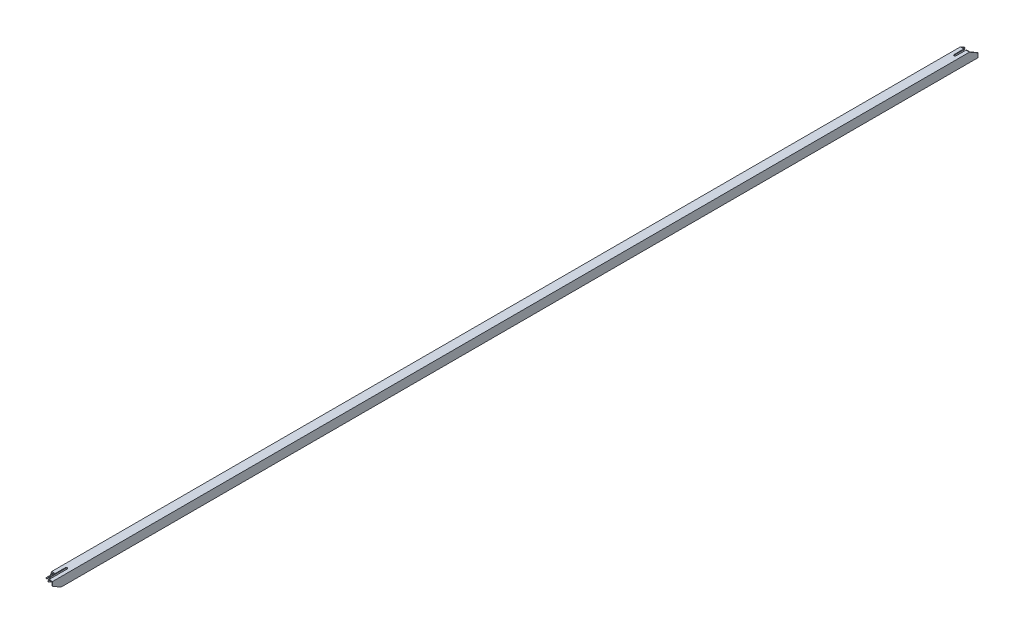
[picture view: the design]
ISO-10303-21;
HEADER;
FILE_DESCRIPTION(('STEP AP214'),'2;1');
FILE_NAME('part.step','',(''),(''),'','','');
FILE_SCHEMA(('AUTOMOTIVE_DESIGN { 1 0 10303 214 1 1 1 1 }'));
ENDSEC;
DATA;
#1=APPLICATION_CONTEXT('core data for automotive mechanical design processes');
#2=APPLICATION_PROTOCOL_DEFINITION('international standard','automotive_design',2000,#1);
#3=PRODUCT_CONTEXT('',#1,'mechanical');
#4=PRODUCT('Part','Part','',(#3));
#5=PRODUCT_RELATED_PRODUCT_CATEGORY('part','',(#4));
#6=PRODUCT_DEFINITION_FORMATION('','',#4);
#7=PRODUCT_DEFINITION_CONTEXT('part definition',#1,'design');
#8=PRODUCT_DEFINITION('design','',#6,#7);
#9=PRODUCT_DEFINITION_SHAPE('','',#8);
#10=(LENGTH_UNIT() NAMED_UNIT(*) SI_UNIT(.MILLI.,.METRE.));
#11=(NAMED_UNIT(*) PLANE_ANGLE_UNIT() SI_UNIT($,.RADIAN.));
#12=(NAMED_UNIT(*) SI_UNIT($,.STERADIAN.) SOLID_ANGLE_UNIT());
#13=UNCERTAINTY_MEASURE_WITH_UNIT(LENGTH_MEASURE(1.E-05),#10,'distance_accuracy_value','');
#14=(GEOMETRIC_REPRESENTATION_CONTEXT(3) GLOBAL_UNCERTAINTY_ASSIGNED_CONTEXT((#13)) GLOBAL_UNIT_ASSIGNED_CONTEXT((#10,
#11,#12)) REPRESENTATION_CONTEXT('',''));
#15=CARTESIAN_POINT('',(0.,0.,0.));
#16=DIRECTION('',(0.,0.,1.));
#17=DIRECTION('',(1.,0.,0.));
#18=AXIS2_PLACEMENT_3D('',#15,#16,#17);
#19=CARTESIAN_POINT('',(7.,-40.,5965.6450767));
#20=DIRECTION('',(1.,0.,0.));
#21=DIRECTION('',(0.,1.,0.));
#22=AXIS2_PLACEMENT_3D('',#19,#20,#21);
#23=PLANE('',#22);
#24=DIRECTION('',(0.,0.,1.));
#25=VECTOR('',#24,1.);
#26=CARTESIAN_POINT('',(7.,26.,2982.82253835));
#27=LINE('',#26,#25);
#28=CARTESIAN_POINT('',(7.,26.,5965.6450767));
#29=VERTEX_POINT('',#28);
#30=CARTESIAN_POINT('',(7.,26.,6085.6450767));
#31=VERTEX_POINT('',#30);
#32=EDGE_CURVE('E392',#29,#31,#27,.T.);
#33=ORIENTED_EDGE('',*,*,#32,.T.);
#34=DIRECTION('',(0.,1.,0.));
#35=VECTOR('',#34,1.);
#36=CARTESIAN_POINT('',(7.,-20.,6085.6450767));
#37=LINE('',#36,#35);
#38=CARTESIAN_POINT('',(7.,30.,6085.6450767));
#39=VERTEX_POINT('',#38);
#40=EDGE_CURVE('E538',#31,#39,#37,.T.);
#41=ORIENTED_EDGE('',*,*,#40,.T.);
#42=DIRECTION('',(0.,0.,1.));
#43=VECTOR('',#42,1.);
#44=CARTESIAN_POINT('',(7.,30.,2982.82253835));
#45=LINE('',#44,#43);
#46=CARTESIAN_POINT('',(7.,30.,5965.6450767));
#47=VERTEX_POINT('',#46);
#48=EDGE_CURVE('E533',#47,#39,#45,.T.);
#49=ORIENTED_EDGE('',*,*,#48,.F.);
#50=DIRECTION('',(0.,1.,0.));
#51=VECTOR('',#50,1.);
#52=CARTESIAN_POINT('',(7.,-40.,5965.6450767));
#53=LINE('',#52,#51);
#54=EDGE_CURVE('E10',#29,#47,#53,.T.);
#55=ORIENTED_EDGE('',*,*,#54,.F.);
#56=EDGE_LOOP('',(#33,#41,#49,#55));
#57=FACE_BOUND('',#56,.T.);
#58=ADVANCED_FACE('F16',(#57),#23,.F.);
#59=CARTESIAN_POINT('',(0.,-40.,5965.6450767));
#60=DIRECTION('',(0.,1.,0.));
#61=DIRECTION('',(0.,0.,1.));
#62=AXIS2_PLACEMENT_3D('',#59,#60,#61);
#63=CYLINDRICAL_SURFACE('',#62,7.);
#64=CARTESIAN_POINT('',(0.,30.,5965.6450767));
#65=DIRECTION('',(0.,1.,0.));
#66=DIRECTION('',(0.,0.,1.));
#67=AXIS2_PLACEMENT_3D('',#64,#65,#66);
#68=CIRCLE('',#67,7.);
#69=CARTESIAN_POINT('',(-7.,30.,5965.6450767));
#70=VERTEX_POINT('',#69);
#71=EDGE_CURVE('E530',#47,#70,#68,.T.);
#72=ORIENTED_EDGE('',*,*,#71,.T.);
#73=DIRECTION('',(0.,1.,0.));
#74=VECTOR('',#73,1.);
#75=CARTESIAN_POINT('',(-7.,-40.,5965.6450767));
#76=LINE('',#75,#74);
#77=CARTESIAN_POINT('',(-7.,26.,5965.6450767));
#78=VERTEX_POINT('',#77);
#79=EDGE_CURVE('E25',#78,#70,#76,.T.);
#80=ORIENTED_EDGE('',*,*,#79,.F.);
#81=CARTESIAN_POINT('',(0.,26.,5965.6450767));
#82=DIRECTION('',(0.,1.,0.));
#83=DIRECTION('',(0.,0.,1.));
#84=AXIS2_PLACEMENT_3D('',#81,#82,#83);
#85=CIRCLE('',#84,7.);
#86=EDGE_CURVE('E543',#29,#78,#85,.T.);
#87=ORIENTED_EDGE('',*,*,#86,.F.);
#88=ORIENTED_EDGE('',*,*,#54,.T.);
#89=EDGE_LOOP('',(#72,#80,#87,#88));
#90=FACE_BOUND('',#89,.T.);
#91=ADVANCED_FACE('F586',(#90),#63,.F.);
#92=CARTESIAN_POINT('',(-7.,-40.,5965.6450767));
#93=DIRECTION('',(1.,0.,0.));
#94=DIRECTION('',(0.,1.,0.));
#95=AXIS2_PLACEMENT_3D('',#92,#93,#94);
#96=PLANE('',#95);
#97=ORIENTED_EDGE('',*,*,#79,.T.);
#98=DIRECTION('',(0.,0.,1.));
#99=VECTOR('',#98,1.);
#100=CARTESIAN_POINT('',(-7.,30.,2982.82253835));
#101=LINE('',#100,#99);
#102=CARTESIAN_POINT('',(-7.,30.,6085.6450767));
#103=VERTEX_POINT('',#102);
#104=EDGE_CURVE('E466',#70,#103,#101,.T.);
#105=ORIENTED_EDGE('',*,*,#104,.T.);
#106=DIRECTION('',(0.,1.,0.));
#107=VECTOR('',#106,1.);
#108=CARTESIAN_POINT('',(-7.,-20.,6085.6450767));
#109=LINE('',#108,#107);
#110=CARTESIAN_POINT('',(-7.,26.,6085.6450767));
#111=VERTEX_POINT('',#110);
#112=EDGE_CURVE('E19',#111,#103,#109,.T.);
#113=ORIENTED_EDGE('',*,*,#112,.F.);
#114=DIRECTION('',(0.,0.,1.));
#115=VECTOR('',#114,1.);
#116=CARTESIAN_POINT('',(-7.,26.,2982.82253835));
#117=LINE('',#116,#115);
#118=EDGE_CURVE('E547',#78,#111,#117,.T.);
#119=ORIENTED_EDGE('',*,*,#118,.F.);
#120=EDGE_LOOP('',(#97,#105,#113,#119));
#121=FACE_BOUND('',#120,.T.);
#122=ADVANCED_FACE('F574',(#121),#96,.T.);
#123=CARTESIAN_POINT('',(0.,0.,6085.6450767));
#124=DIRECTION('',(0.,0.,1.));
#125=DIRECTION('',(1.,0.,0.));
#126=AXIS2_PLACEMENT_3D('',#123,#124,#125);
#127=PLANE('',#126);
#128=ORIENTED_EDGE('',*,*,#112,.T.);
#129=DIRECTION('',(-1.,0.,0.));
#130=VECTOR('',#129,1.);
#131=CARTESIAN_POINT('',(30.,30.,6085.6450767));
#132=LINE('',#131,#130);
#133=CARTESIAN_POINT('',(-13.,30.,6085.6450767));
#134=VERTEX_POINT('',#133);
#135=EDGE_CURVE('E462',#103,#134,#132,.T.);
#136=ORIENTED_EDGE('',*,*,#135,.T.);
#137=DIRECTION('',(0.,-1.,0.));
#138=VECTOR('',#137,1.);
#139=CARTESIAN_POINT('',(-13.,1310.449409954,6085.6450767));
#140=LINE('',#139,#138);
#141=CARTESIAN_POINT('',(-13.,26.,6085.6450767));
#142=VERTEX_POINT('',#141);
#143=EDGE_CURVE('E369',#134,#142,#140,.T.);
#144=ORIENTED_EDGE('',*,*,#143,.T.);
#145=DIRECTION('',(-1.,0.,0.));
#146=VECTOR('',#145,1.);
#147=CARTESIAN_POINT('',(26.,26.,6085.6450767));
#148=LINE('',#147,#146);
#149=EDGE_CURVE('E551',#111,#142,#148,.T.);
#150=ORIENTED_EDGE('',*,*,#149,.F.);
#151=EDGE_LOOP('',(#128,#136,#144,#150));
#152=FACE_BOUND('',#151,.T.);
#153=ADVANCED_FACE('F570',(#152),#127,.T.);
#154=CARTESIAN_POINT('',(-13.,2620.898819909,4549.014549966));
#155=DIRECTION('',(-1.,0.,0.));
#156=DIRECTION('',(0.,0.,1.));
#157=AXIS2_PLACEMENT_3D('',#154,#155,#156);
#158=PLANE('',#157);
#159=DIRECTION('',(0.,0.,-1.));
#160=VECTOR('',#159,1.);
#161=CARTESIAN_POINT('',(-13.,30.,2274.507274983));
#162=LINE('',#161,#160);
#163=CARTESIAN_POINT('',(-13.,30.,6033.874366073));
#164=VERTEX_POINT('',#163);
#165=EDGE_CURVE('E467',#134,#164,#162,.T.);
#166=ORIENTED_EDGE('',*,*,#165,.T.);
#167=DIRECTION('',(0.,-0.867615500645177,0.497235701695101));
#168=VECTOR('',#167,1.);
#169=CARTESIAN_POINT('',(-13.,2620.898819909,4549.014549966));
#170=LINE('',#169,#168);
#171=CARTESIAN_POINT('',(-13.,26.,6036.166790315));
#172=VERTEX_POINT('',#171);
#173=EDGE_CURVE('E368',#164,#172,#170,.T.);
#174=ORIENTED_EDGE('',*,*,#173,.T.);
#175=DIRECTION('',(0.,0.,-1.));
#176=VECTOR('',#175,1.);
#177=CARTESIAN_POINT('',(-13.,26.,2274.507274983));
#178=LINE('',#177,#176);
#179=EDGE_CURVE('E555',#142,#172,#178,.T.);
#180=ORIENTED_EDGE('',*,*,#179,.F.);
#181=ORIENTED_EDGE('',*,*,#143,.F.);
#182=EDGE_LOOP('',(#166,#174,#180,#181));
#183=FACE_BOUND('',#182,.T.);
#184=ADVANCED_FACE('F580',(#183),#158,.T.);
#185=CARTESIAN_POINT('',(-15.,2620.898819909,4549.014549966));
#186=DIRECTION('',(0.,-0.867615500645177,0.497235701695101));
#187=DIRECTION('',(-1.,0.,0.));
#188=AXIS2_PLACEMENT_3D('',#185,#186,#187);
#189=CYLINDRICAL_SURFACE('',#188,2.);
#190=CARTESIAN_POINT('',(-15.,26.,6036.166790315));
#191=DIRECTION('',(0.,-1.,0.));
#192=DIRECTION('',(0.,0.,1.));
#193=AXIS2_PLACEMENT_3D('',#190,#191,#192);
#194=ELLIPSE('',#193,2.305168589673,2.);
#195=CARTESIAN_POINT('',(-15.,26.,6033.861621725));
#196=VERTEX_POINT('',#195);
#197=EDGE_CURVE('E504',#196,#172,#194,.T.);
#198=ORIENTED_EDGE('',*,*,#197,.T.);
#199=ORIENTED_EDGE('',*,*,#173,.F.);
#200=CARTESIAN_POINT('',(-15.,30.,6033.874366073));
#201=DIRECTION('',(0.,-1.,0.));
#202=DIRECTION('',(0.,0.,1.));
#203=AXIS2_PLACEMENT_3D('',#200,#201,#202);
#204=ELLIPSE('',#203,2.305168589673,2.);
#205=CARTESIAN_POINT('',(-15.,30.,6031.569197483));
#206=VERTEX_POINT('',#205);
#207=EDGE_CURVE('E521',#206,#164,#204,.T.);
#208=ORIENTED_EDGE('',*,*,#207,.F.);
#209=DIRECTION('',(0.,-0.867615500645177,0.497235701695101));
#210=VECTOR('',#209,1.);
#211=CARTESIAN_POINT('',(-15.,2619.904348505,4547.279318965));
#212=LINE('',#211,#210);
#213=EDGE_CURVE('E478',#206,#196,#212,.T.);
#214=ORIENTED_EDGE('',*,*,#213,.T.);
#215=EDGE_LOOP('',(#198,#199,#208,#214));
#216=FACE_BOUND('',#215,.T.);
#217=ADVANCED_FACE('F779',(#216),#189,.F.);
#218=CARTESIAN_POINT('',(-7.,-40.,-1.));
#219=DIRECTION('',(1.,0.,0.));
#220=DIRECTION('',(0.,1.,0.));
#221=AXIS2_PLACEMENT_3D('',#218,#219,#220);
#222=PLANE('',#221);
#223=DIRECTION('',(0.,1.,0.));
#224=VECTOR('',#223,1.);
#225=CARTESIAN_POINT('',(-7.,-40.,120.));
#226=LINE('',#225,#224);
#227=CARTESIAN_POINT('',(-7.,26.,120.));
#228=VERTEX_POINT('',#227);
#229=CARTESIAN_POINT('',(-7.,30.,120.));
#230=VERTEX_POINT('',#229);
#231=EDGE_CURVE('E370',#228,#230,#226,.T.);
#232=ORIENTED_EDGE('',*,*,#231,.F.);
#233=DIRECTION('',(0.,0.,1.));
#234=VECTOR('',#233,1.);
#235=CARTESIAN_POINT('',(-7.,26.,-0.5));
#236=LINE('',#235,#234);
#237=CARTESIAN_POINT('',(-7.,26.,49.389058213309));
#238=VERTEX_POINT('',#237);
#239=EDGE_CURVE('E499',#238,#228,#236,.T.);
#240=ORIENTED_EDGE('',*,*,#239,.F.);
#241=DIRECTION('',(0.,-0.497235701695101,-0.867615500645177));
#242=VECTOR('',#241,1.);
#243=CARTESIAN_POINT('',(-7.,-6.895802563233,-8.01009497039));
#244=LINE('',#243,#242);
#245=CARTESIAN_POINT('',(-7.,30.,56.368569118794));
#246=VERTEX_POINT('',#245);
#247=EDGE_CURVE('E393',#246,#238,#244,.T.);
#248=ORIENTED_EDGE('',*,*,#247,.F.);
#249=DIRECTION('',(0.,0.,1.));
#250=VECTOR('',#249,1.);
#251=CARTESIAN_POINT('',(-7.,30.,-0.5));
#252=LINE('',#251,#250);
#253=EDGE_CURVE('E427',#246,#230,#252,.T.);
#254=ORIENTED_EDGE('',*,*,#253,.T.);
#255=EDGE_LOOP('',(#232,#240,#248,#254));
#256=FACE_BOUND('',#255,.T.);
#257=ADVANCED_FACE('F764',(#256),#222,.T.);
#258=CARTESIAN_POINT('',(0.,-40.,120.));
#259=DIRECTION('',(0.,1.,0.));
#260=DIRECTION('',(0.,0.,1.));
#261=AXIS2_PLACEMENT_3D('',#258,#259,#260);
#262=CYLINDRICAL_SURFACE('',#261,7.);
#263=CARTESIAN_POINT('',(0.,26.,120.));
#264=DIRECTION('',(0.,1.,0.));
#265=DIRECTION('',(0.,0.,1.));
#266=AXIS2_PLACEMENT_3D('',#263,#264,#265);
#267=CIRCLE('',#266,7.);
#268=CARTESIAN_POINT('',(0.,26.,127.));
#269=VERTEX_POINT('',#268);
#270=EDGE_CURVE('E503',#228,#269,#267,.T.);
#271=ORIENTED_EDGE('',*,*,#270,.F.);
#272=ORIENTED_EDGE('',*,*,#231,.T.);
#273=CARTESIAN_POINT('',(0.,30.,120.));
#274=DIRECTION('',(0.,1.,0.));
#275=DIRECTION('',(0.,0.,1.));
#276=AXIS2_PLACEMENT_3D('',#273,#274,#275);
#277=CIRCLE('',#276,7.);
#278=CARTESIAN_POINT('',(0.,30.,127.));
#279=VERTEX_POINT('',#278);
#280=EDGE_CURVE('E511',#230,#279,#277,.T.);
#281=ORIENTED_EDGE('',*,*,#280,.T.);
#282=DIRECTION('',(0.,1.,0.));
#283=VECTOR('',#282,1.);
#284=CARTESIAN_POINT('',(0.,-40.,127.));
#285=LINE('',#284,#283);
#286=EDGE_CURVE('E51',#269,#279,#285,.T.);
#287=ORIENTED_EDGE('',*,*,#286,.F.);
#288=EDGE_LOOP('',(#271,#272,#281,#287));
#289=FACE_BOUND('',#288,.T.);
#290=ADVANCED_FACE('F759',(#289),#262,.F.);
#291=CARTESIAN_POINT('',(0.,-40.,120.));
#292=DIRECTION('',(0.,1.,0.));
#293=DIRECTION('',(0.,0.,1.));
#294=AXIS2_PLACEMENT_3D('',#291,#292,#293);
#295=CYLINDRICAL_SURFACE('',#294,7.);
#296=DIRECTION('',(0.,1.,0.));
#297=VECTOR('',#296,1.);
#298=CARTESIAN_POINT('',(7.,-40.,120.));
#299=LINE('',#298,#297);
#300=CARTESIAN_POINT('',(7.,26.,120.));
#301=VERTEX_POINT('',#300);
#302=CARTESIAN_POINT('',(7.,30.,120.));
#303=VERTEX_POINT('',#302);
#304=EDGE_CURVE('E38',#301,#303,#299,.T.);
#305=ORIENTED_EDGE('',*,*,#304,.F.);
#306=CARTESIAN_POINT('',(0.,26.,120.));
#307=DIRECTION('',(0.,1.,0.));
#308=DIRECTION('',(0.,0.,1.));
#309=AXIS2_PLACEMENT_3D('',#306,#307,#308);
#310=CIRCLE('',#309,7.);
#311=EDGE_CURVE('E561',#269,#301,#310,.T.);
#312=ORIENTED_EDGE('',*,*,#311,.F.);
#313=ORIENTED_EDGE('',*,*,#286,.T.);
#314=CARTESIAN_POINT('',(0.,30.,120.));
#315=DIRECTION('',(0.,1.,0.));
#316=DIRECTION('',(0.,0.,1.));
#317=AXIS2_PLACEMENT_3D('',#314,#315,#316);
#318=CIRCLE('',#317,7.);
#319=EDGE_CURVE('E508',#279,#303,#318,.T.);
#320=ORIENTED_EDGE('',*,*,#319,.T.);
#321=EDGE_LOOP('',(#305,#312,#313,#320));
#322=FACE_BOUND('',#321,.T.);
#323=ADVANCED_FACE('F758',(#322),#295,.F.);
#324=CARTESIAN_POINT('',(7.,-40.,-1.));
#325=DIRECTION('',(1.,0.,0.));
#326=DIRECTION('',(0.,1.,0.));
#327=AXIS2_PLACEMENT_3D('',#324,#325,#326);
#328=PLANE('',#327);
#329=DIRECTION('',(0.,0.,1.));
#330=VECTOR('',#329,1.);
#331=CARTESIAN_POINT('',(7.,30.,-0.5));
#332=LINE('',#331,#330);
#333=CARTESIAN_POINT('',(7.,30.,56.368569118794));
#334=VERTEX_POINT('',#333);
#335=EDGE_CURVE('E498',#334,#303,#332,.T.);
#336=ORIENTED_EDGE('',*,*,#335,.F.);
#337=DIRECTION('',(0.,-0.497235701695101,-0.867615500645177));
#338=VECTOR('',#337,1.);
#339=CARTESIAN_POINT('',(7.,-6.895802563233,-8.01009497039));
#340=LINE('',#339,#338);
#341=CARTESIAN_POINT('',(7.,26.,49.389058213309));
#342=VERTEX_POINT('',#341);
#343=EDGE_CURVE('E490',#334,#342,#340,.T.);
#344=ORIENTED_EDGE('',*,*,#343,.T.);
#345=DIRECTION('',(0.,0.,1.));
#346=VECTOR('',#345,1.);
#347=CARTESIAN_POINT('',(7.,26.,-0.5));
#348=LINE('',#347,#346);
#349=EDGE_CURVE('E407',#342,#301,#348,.T.);
#350=ORIENTED_EDGE('',*,*,#349,.T.);
#351=ORIENTED_EDGE('',*,*,#304,.T.);
#352=EDGE_LOOP('',(#336,#344,#350,#351));
#353=FACE_BOUND('',#352,.T.);
#354=ADVANCED_FACE('F757',(#353),#328,.F.);
#355=CARTESIAN_POINT('',(26.,26.,0.));
#356=DIRECTION('',(0.,-1.,0.));
#357=DIRECTION('',(0.,0.,-1.));
#358=AXIS2_PLACEMENT_3D('',#355,#356,#357);
#359=PLANE('',#358);
#360=DIRECTION('',(-1.,0.,0.));
#361=VECTOR('',#360,1.);
#362=CARTESIAN_POINT('',(-9.5,26.,49.389058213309));
#363=LINE('',#362,#361);
#364=CARTESIAN_POINT('',(26.,26.,49.389058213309));
#365=VERTEX_POINT('',#364);
#366=EDGE_CURVE('E486',#365,#342,#363,.T.);
#367=ORIENTED_EDGE('',*,*,#366,.F.);
#368=DIRECTION('',(0.,0.,1.));
#369=VECTOR('',#368,1.);
#370=CARTESIAN_POINT('',(26.,26.,0.));
#371=LINE('',#370,#369);
#372=CARTESIAN_POINT('',(26.,26.,6085.6450767));
#373=VERTEX_POINT('',#372);
#374=EDGE_CURVE('E470',#365,#373,#371,.T.);
#375=ORIENTED_EDGE('',*,*,#374,.T.);
#376=DIRECTION('',(-1.,0.,0.));
#377=VECTOR('',#376,1.);
#378=CARTESIAN_POINT('',(26.,26.,6085.6450767));
#379=LINE('',#378,#377);
#380=EDGE_CURVE('E473',#373,#31,#379,.T.);
#381=ORIENTED_EDGE('',*,*,#380,.T.);
#382=ORIENTED_EDGE('',*,*,#32,.F.);
#383=ORIENTED_EDGE('',*,*,#86,.T.);
#384=ORIENTED_EDGE('',*,*,#118,.T.);
#385=ORIENTED_EDGE('',*,*,#149,.T.);
#386=ORIENTED_EDGE('',*,*,#179,.T.);
#387=ORIENTED_EDGE('',*,*,#197,.F.);
#388=DIRECTION('',(-1.,0.,0.));
#389=VECTOR('',#388,1.);
#390=CARTESIAN_POINT('',(-24.5,26.,6033.861621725));
#391=LINE('',#390,#389);
#392=CARTESIAN_POINT('',(-26.,26.,6033.861621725));
#393=VERTEX_POINT('',#392);
#394=EDGE_CURVE('E482',#196,#393,#391,.T.);
#395=ORIENTED_EDGE('',*,*,#394,.T.);
#396=DIRECTION('',(0.,0.,1.));
#397=VECTOR('',#396,1.);
#398=CARTESIAN_POINT('',(-26.,26.,0.));
#399=LINE('',#398,#397);
#400=CARTESIAN_POINT('',(-26.,26.,49.389058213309));
#401=VERTEX_POINT('',#400);
#402=EDGE_CURVE('E413',#401,#393,#399,.T.);
#403=ORIENTED_EDGE('',*,*,#402,.F.);
#404=DIRECTION('',(-1.,0.,0.));
#405=VECTOR('',#404,1.);
#406=CARTESIAN_POINT('',(-9.5,26.,49.389058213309));
#407=LINE('',#406,#405);
#408=EDGE_CURVE('E389',#238,#401,#407,.T.);
#409=ORIENTED_EDGE('',*,*,#408,.F.);
#410=ORIENTED_EDGE('',*,*,#239,.T.);
#411=ORIENTED_EDGE('',*,*,#270,.T.);
#412=ORIENTED_EDGE('',*,*,#311,.T.);
#413=ORIENTED_EDGE('',*,*,#349,.F.);
#414=EDGE_LOOP('',(#367,#375,#381,#382,#383,#384,#385,#386,#387,#395,#403,#409,#410,#411,#412,#413));
#415=FACE_BOUND('',#414,.T.);
#416=ADVANCED_FACE('F583',(#415),#359,.T.);
#417=CARTESIAN_POINT('',(-45.,-1.73523100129,0.994471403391));
#418=DIRECTION('',(0.,-0.867615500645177,0.497235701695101));
#419=DIRECTION('',(-1.,0.,0.));
#420=AXIS2_PLACEMENT_3D('',#417,#418,#419);
#421=PLANE('',#420);
#422=ORIENTED_EDGE('',*,*,#247,.T.);
#423=ORIENTED_EDGE('',*,*,#408,.T.);
#424=DIRECTION('',(0.,-0.497235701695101,-0.867615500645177));
#425=VECTOR('',#424,1.);
#426=CARTESIAN_POINT('',(-26.,1.478932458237,6.602793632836));
#427=LINE('',#426,#425);
#428=CARTESIAN_POINT('',(-26.,14.176311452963,28.758167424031));
#429=VERTEX_POINT('',#428);
#430=EDGE_CURVE('E418',#401,#429,#427,.T.);
#431=ORIENTED_EDGE('',*,*,#430,.T.);
#432=DIRECTION('',(-1.,0.,0.));
#433=VECTOR('',#432,1.);
#434=CARTESIAN_POINT('',(-30.,14.176311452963,28.758167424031));
#435=LINE('',#434,#433);
#436=CARTESIAN_POINT('',(-30.,14.176311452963,28.758167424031));
#437=VERTEX_POINT('',#436);
#438=EDGE_CURVE('E441',#429,#437,#435,.T.);
#439=ORIENTED_EDGE('',*,*,#438,.T.);
#440=DIRECTION('',(0.,-0.497235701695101,-0.867615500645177));
#441=VECTOR('',#440,1.);
#442=CARTESIAN_POINT('',(-30.,1.973419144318,7.465612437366));
#443=LINE('',#442,#441);
#444=CARTESIAN_POINT('',(-30.,30.,56.368569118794));
#445=VERTEX_POINT('',#444);
#446=EDGE_CURVE('E446',#445,#437,#443,.T.);
#447=ORIENTED_EDGE('',*,*,#446,.F.);
#448=DIRECTION('',(-1.,0.,0.));
#449=VECTOR('',#448,1.);
#450=CARTESIAN_POINT('',(-7.5,30.,56.368569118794));
#451=LINE('',#450,#449);
#452=EDGE_CURVE('E423',#246,#445,#451,.T.);
#453=ORIENTED_EDGE('',*,*,#452,.F.);
#454=EDGE_LOOP('',(#422,#423,#431,#439,#447,#453));
#455=FACE_BOUND('',#454,.T.);
#456=ADVANCED_FACE('F767',(#455),#421,.F.);
#457=CARTESIAN_POINT('',(-75.,2619.904348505,4547.279318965));
#458=DIRECTION('',(0.,0.497235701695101,0.867615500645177));
#459=DIRECTION('',(1.,0.,0.));
#460=AXIS2_PLACEMENT_3D('',#457,#458,#459);
#461=PLANE('',#460);
#462=ORIENTED_EDGE('',*,*,#213,.F.);
#463=DIRECTION('',(-1.,0.,0.));
#464=VECTOR('',#463,1.);
#465=CARTESIAN_POINT('',(-22.5,30.,6031.569197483));
#466=LINE('',#465,#464);
#467=CARTESIAN_POINT('',(-30.,30.,6031.569197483));
#468=VERTEX_POINT('',#467);
#469=EDGE_CURVE('E426',#206,#468,#466,.T.);
#470=ORIENTED_EDGE('',*,*,#469,.T.);
#471=DIRECTION('',(0.,-0.867615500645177,0.497235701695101));
#472=VECTOR('',#471,1.);
#473=CARTESIAN_POINT('',(-30.,2625.990005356,4543.791592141));
#474=LINE('',#473,#472);
#475=CARTESIAN_POINT('',(-30.,-14.17631145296,6056.886909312));
#476=VERTEX_POINT('',#475);
#477=EDGE_CURVE('E433',#468,#476,#474,.T.);
#478=ORIENTED_EDGE('',*,*,#477,.T.);
#479=DIRECTION('',(-1.,0.,0.));
#480=VECTOR('',#479,1.);
#481=CARTESIAN_POINT('',(-60.,-14.17631145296,6056.886909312));
#482=LINE('',#481,#480);
#483=CARTESIAN_POINT('',(-26.,-14.17631145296,6056.886909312));
#484=VERTEX_POINT('',#483);
#485=EDGE_CURVE('E422',#484,#476,#482,.T.);
#486=ORIENTED_EDGE('',*,*,#485,.F.);
#487=DIRECTION('',(0.,-0.867615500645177,0.497235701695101));
#488=VECTOR('',#487,1.);
#489=CARTESIAN_POINT('',(-26.,2624.484492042,4544.654410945));
#490=LINE('',#489,#488);
#491=EDGE_CURVE('E417',#393,#484,#490,.T.);
#492=ORIENTED_EDGE('',*,*,#491,.F.);
#493=ORIENTED_EDGE('',*,*,#394,.F.);
#494=EDGE_LOOP('',(#462,#470,#478,#486,#492,#493));
#495=FACE_BOUND('',#494,.T.);
#496=ADVANCED_FACE('F774',(#495),#461,.T.);
#497=CARTESIAN_POINT('',(-26.,26.,0.));
#498=DIRECTION('',(1.,0.,0.));
#499=DIRECTION('',(0.,1.,0.));
#500=AXIS2_PLACEMENT_3D('',#497,#498,#499);
#501=PLANE('',#500);
#502=ORIENTED_EDGE('',*,*,#430,.F.);
#503=ORIENTED_EDGE('',*,*,#402,.T.);
#504=ORIENTED_EDGE('',*,*,#491,.T.);
#505=DIRECTION('',(0.,0.497235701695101,0.867615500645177));
#506=VECTOR('',#505,1.);
#507=CARTESIAN_POINT('',(-26.,-1330.625700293,3759.843692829));
#508=LINE('',#507,#506);
#509=CARTESIAN_POINT('',(-26.,-26.,6036.256018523));
#510=VERTEX_POINT('',#509);
#511=EDGE_CURVE('E412',#510,#484,#508,.T.);
#512=ORIENTED_EDGE('',*,*,#511,.F.);
#513=DIRECTION('',(0.,0.,1.));
#514=VECTOR('',#513,1.);
#515=CARTESIAN_POINT('',(-26.,-26.,0.));
#516=LINE('',#515,#514);
#517=CARTESIAN_POINT('',(-26.,-26.,51.783455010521));
#518=VERTEX_POINT('',#517);
#519=EDGE_CURVE('E428',#518,#510,#516,.T.);
#520=ORIENTED_EDGE('',*,*,#519,.F.);
#521=DIRECTION('',(0.,0.867615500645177,-0.497235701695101));
#522=VECTOR('',#521,1.);
#523=CARTESIAN_POINT('',(-26.,30.903071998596,19.171959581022));
#524=LINE('',#523,#522);
#525=EDGE_CURVE('E449',#518,#429,#524,.T.);
#526=ORIENTED_EDGE('',*,*,#525,.T.);
#527=EDGE_LOOP('',(#502,#503,#504,#512,#520,#526));
#528=FACE_BOUND('',#527,.T.);
#529=ADVANCED_FACE('F920',(#528),#501,.T.);
#530=CARTESIAN_POINT('',(0.,0.,6085.6450767));
#531=DIRECTION('',(0.,0.,1.));
#532=DIRECTION('',(1.,0.,0.));
#533=AXIS2_PLACEMENT_3D('',#530,#531,#532);
#534=PLANE('',#533);
#535=DIRECTION('',(0.,1.,0.));
#536=VECTOR('',#535,1.);
#537=CARTESIAN_POINT('',(26.,-26.,6085.6450767));
#538=LINE('',#537,#536);
#539=CARTESIAN_POINT('',(26.,2.305168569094,6085.6450767));
#540=VERTEX_POINT('',#539);
#541=EDGE_CURVE('E339',#540,#373,#538,.T.);
#542=ORIENTED_EDGE('',*,*,#541,.F.);
#543=DIRECTION('',(-1.,0.,0.));
#544=VECTOR('',#543,1.);
#545=CARTESIAN_POINT('',(-22.5,2.305168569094,6085.6450767));
#546=LINE('',#545,#544);
#547=CARTESIAN_POINT('',(30.,2.305168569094,6085.6450767));
#548=VERTEX_POINT('',#547);
#549=EDGE_CURVE('E332',#548,#540,#546,.T.);
#550=ORIENTED_EDGE('',*,*,#549,.F.);
#551=DIRECTION('',(0.,1.,0.));
#552=VECTOR('',#551,1.);
#553=CARTESIAN_POINT('',(30.,-30.,6085.6450767));
#554=LINE('',#553,#552);
#555=CARTESIAN_POINT('',(30.,30.,6085.6450767));
#556=VERTEX_POINT('',#555);
#557=EDGE_CURVE('E336',#548,#556,#554,.T.);
#558=ORIENTED_EDGE('',*,*,#557,.T.);
#559=DIRECTION('',(-1.,0.,0.));
#560=VECTOR('',#559,1.);
#561=CARTESIAN_POINT('',(30.,30.,6085.6450767));
#562=LINE('',#561,#560);
#563=EDGE_CURVE('E326',#556,#39,#562,.T.);
#564=ORIENTED_EDGE('',*,*,#563,.T.);
#565=ORIENTED_EDGE('',*,*,#40,.F.);
#566=ORIENTED_EDGE('',*,*,#380,.F.);
#567=EDGE_LOOP('',(#542,#550,#558,#564,#565,#566));
#568=FACE_BOUND('',#567,.T.);
#569=ADVANCED_FACE('F334',(#568),#534,.T.);
#570=CARTESIAN_POINT('',(30.,30.,0.));
#571=DIRECTION('',(0.,-1.,0.));
#572=DIRECTION('',(0.,0.,-1.));
#573=AXIS2_PLACEMENT_3D('',#570,#571,#572);
#574=PLANE('',#573);
#575=ORIENTED_EDGE('',*,*,#335,.T.);
#576=ORIENTED_EDGE('',*,*,#319,.F.);
#577=ORIENTED_EDGE('',*,*,#280,.F.);
#578=ORIENTED_EDGE('',*,*,#253,.F.);
#579=ORIENTED_EDGE('',*,*,#452,.T.);
#580=DIRECTION('',(0.,0.,1.));
#581=VECTOR('',#580,1.);
#582=CARTESIAN_POINT('',(-30.,30.,0.));
#583=LINE('',#582,#581);
#584=EDGE_CURVE('E436',#445,#468,#583,.T.);
#585=ORIENTED_EDGE('',*,*,#584,.T.);
#586=ORIENTED_EDGE('',*,*,#469,.F.);
#587=ORIENTED_EDGE('',*,*,#207,.T.);
#588=ORIENTED_EDGE('',*,*,#165,.F.);
#589=ORIENTED_EDGE('',*,*,#135,.F.);
#590=ORIENTED_EDGE('',*,*,#104,.F.);
#591=ORIENTED_EDGE('',*,*,#71,.F.);
#592=ORIENTED_EDGE('',*,*,#48,.T.);
#593=ORIENTED_EDGE('',*,*,#563,.F.);
#594=DIRECTION('',(0.,0.,1.));
#595=VECTOR('',#594,1.);
#596=CARTESIAN_POINT('',(30.,30.,0.));
#597=LINE('',#596,#595);
#598=CARTESIAN_POINT('',(30.,30.,56.368569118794));
#599=VERTEX_POINT('',#598);
#600=EDGE_CURVE('E358',#599,#556,#597,.T.);
#601=ORIENTED_EDGE('',*,*,#600,.F.);
#602=DIRECTION('',(-1.,0.,0.));
#603=VECTOR('',#602,1.);
#604=CARTESIAN_POINT('',(-7.5,30.,56.368569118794));
#605=LINE('',#604,#603);
#606=EDGE_CURVE('E494',#599,#334,#605,.T.);
#607=ORIENTED_EDGE('',*,*,#606,.T.);
#608=EDGE_LOOP('',(#575,#576,#577,#578,#579,#585,#586,#587,#588,#589,#590,#591,#592,#593,#601,#607));
#609=FACE_BOUND('',#608,.T.);
#610=ADVANCED_FACE('F576',(#609),#574,.F.);
#611=CARTESIAN_POINT('',(-45.,-1.73523100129,0.994471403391));
#612=DIRECTION('',(0.,-0.867615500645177,0.497235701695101));
#613=DIRECTION('',(-1.,0.,0.));
#614=AXIS2_PLACEMENT_3D('',#611,#612,#613);
#615=PLANE('',#614);
#616=ORIENTED_EDGE('',*,*,#366,.T.);
#617=ORIENTED_EDGE('',*,*,#343,.F.);
#618=ORIENTED_EDGE('',*,*,#606,.F.);
#619=DIRECTION('',(0.,0.497235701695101,0.867615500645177));
#620=VECTOR('',#619,1.);
#621=CARTESIAN_POINT('',(30.,-5.443881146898,-5.476669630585));
#622=LINE('',#621,#620);
#623=CARTESIAN_POINT('',(30.,-2.305168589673,0.));
#624=VERTEX_POINT('',#623);
#625=EDGE_CURVE('E364',#624,#599,#622,.T.);
#626=ORIENTED_EDGE('',*,*,#625,.F.);
#627=DIRECTION('',(1.,0.,0.));
#628=VECTOR('',#627,1.);
#629=CARTESIAN_POINT('',(-22.5,-2.305168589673,0.));
#630=LINE('',#629,#628);
#631=CARTESIAN_POINT('',(26.,-2.305168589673,0.));
#632=VERTEX_POINT('',#631);
#633=EDGE_CURVE('E733',#632,#624,#630,.T.);
#634=ORIENTED_EDGE('',*,*,#633,.F.);
#635=DIRECTION('',(0.,0.497235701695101,0.867615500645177));
#636=VECTOR('',#635,1.);
#637=CARTESIAN_POINT('',(26.,-4.949394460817,-4.613850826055));
#638=LINE('',#637,#636);
#639=EDGE_CURVE('E477',#632,#365,#638,.T.);
#640=ORIENTED_EDGE('',*,*,#639,.T.);
#641=EDGE_LOOP('',(#616,#617,#618,#626,#634,#640));
#642=FACE_BOUND('',#641,.T.);
#643=ADVANCED_FACE('F752',(#642),#615,.F.);
#644=CARTESIAN_POINT('',(26.,-26.,0.));
#645=DIRECTION('',(-1.,0.,0.));
#646=DIRECTION('',(0.,0.,1.));
#647=AXIS2_PLACEMENT_3D('',#644,#645,#646);
#648=PLANE('',#647);
#649=DIRECTION('',(0.,1.,0.));
#650=VECTOR('',#649,1.);
#651=CARTESIAN_POINT('',(26.,-26.,0.));
#652=LINE('',#651,#650);
#653=CARTESIAN_POINT('',(26.,-26.,0.));
#654=VERTEX_POINT('',#653);
#655=EDGE_CURVE('E729',#654,#632,#652,.T.);
#656=ORIENTED_EDGE('',*,*,#655,.F.);
#657=DIRECTION('',(0.,0.,1.));
#658=VECTOR('',#657,1.);
#659=CARTESIAN_POINT('',(26.,-26.,0.));
#660=LINE('',#659,#658);
#661=CARTESIAN_POINT('',(26.,-26.,6036.256018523));
#662=VERTEX_POINT('',#661);
#663=EDGE_CURVE('E431',#654,#662,#660,.T.);
#664=ORIENTED_EDGE('',*,*,#663,.T.);
#665=DIRECTION('',(0.,-0.497235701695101,-0.867615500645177));
#666=VECTOR('',#665,1.);
#667=CARTESIAN_POINT('',(26.,-1337.054027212,3748.627048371));
#668=LINE('',#667,#666);
#669=EDGE_CURVE('E344',#540,#662,#668,.T.);
#670=ORIENTED_EDGE('',*,*,#669,.F.);
#671=ORIENTED_EDGE('',*,*,#541,.T.);
#672=ORIENTED_EDGE('',*,*,#374,.F.);
#673=ORIENTED_EDGE('',*,*,#639,.F.);
#674=EDGE_LOOP('',(#656,#664,#670,#671,#672,#673));
#675=FACE_BOUND('',#674,.T.);
#676=ADVANCED_FACE('F944',(#675),#648,.T.);
#677=CARTESIAN_POINT('',(-26.,-26.,0.));
#678=DIRECTION('',(0.,1.,0.));
#679=DIRECTION('',(1.,0.,0.));
#680=AXIS2_PLACEMENT_3D('',#677,#678,#679);
#681=PLANE('',#680);
#682=DIRECTION('',(1.,0.,0.));
#683=VECTOR('',#682,1.);
#684=CARTESIAN_POINT('',(-26.,-26.,0.));
#685=LINE('',#684,#683);
#686=CARTESIAN_POINT('',(-13.,-26.,0.));
#687=VERTEX_POINT('',#686);
#688=CARTESIAN_POINT('',(-7.,-26.,0.));
#689=VERTEX_POINT('',#688);
#690=EDGE_CURVE('E686',#687,#689,#685,.T.);
#691=ORIENTED_EDGE('',*,*,#690,.F.);
#692=DIRECTION('',(0.,0.,1.));
#693=VECTOR('',#692,1.);
#694=CARTESIAN_POINT('',(-13.,-26.,-15.99764671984));
#695=LINE('',#694,#693);
#696=CARTESIAN_POINT('',(-13.,-26.,49.478286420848));
#697=VERTEX_POINT('',#696);
#698=EDGE_CURVE('E432',#687,#697,#695,.T.);
#699=ORIENTED_EDGE('',*,*,#698,.T.);
#700=CARTESIAN_POINT('',(-15.,-26.,49.478286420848));
#701=DIRECTION('',(0.,1.,0.));
#702=DIRECTION('',(0.,0.,1.));
#703=AXIS2_PLACEMENT_3D('',#700,#701,#702);
#704=ELLIPSE('',#703,2.305168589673,2.);
#705=CARTESIAN_POINT('',(-15.,-26.,51.783455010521));
#706=VERTEX_POINT('',#705);
#707=EDGE_CURVE('E453',#706,#697,#704,.T.);
#708=ORIENTED_EDGE('',*,*,#707,.F.);
#709=DIRECTION('',(-1.,0.,0.));
#710=VECTOR('',#709,1.);
#711=CARTESIAN_POINT('',(-20.5,-26.,51.783455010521));
#712=LINE('',#711,#710);
#713=EDGE_CURVE('E442',#706,#518,#712,.T.);
#714=ORIENTED_EDGE('',*,*,#713,.T.);
#715=ORIENTED_EDGE('',*,*,#519,.T.);
#716=DIRECTION('',(-1.,0.,0.));
#717=VECTOR('',#716,1.);
#718=CARTESIAN_POINT('',(-35.5,-26.,6036.256018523));
#719=LINE('',#718,#717);
#720=CARTESIAN_POINT('',(-7.,-26.,6036.256018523));
#721=VERTEX_POINT('',#720);
#722=EDGE_CURVE('E408',#721,#510,#719,.T.);
#723=ORIENTED_EDGE('',*,*,#722,.F.);
#724=DIRECTION('',(0.,0.,-1.));
#725=VECTOR('',#724,1.);
#726=CARTESIAN_POINT('',(-7.,-26.,2982.82253835));
#727=LINE('',#726,#725);
#728=CARTESIAN_POINT('',(-7.,-26.,5965.6450767));
#729=VERTEX_POINT('',#728);
#730=EDGE_CURVE('E400',#721,#729,#727,.T.);
#731=ORIENTED_EDGE('',*,*,#730,.T.);
#732=CARTESIAN_POINT('',(0.,-26.,5965.6450767));
#733=DIRECTION('',(0.,1.,0.));
#734=DIRECTION('',(0.,0.,1.));
#735=AXIS2_PLACEMENT_3D('',#732,#733,#734);
#736=CIRCLE('',#735,7.);
#737=CARTESIAN_POINT('',(7.,-26.,5965.6450767));
#738=VERTEX_POINT('',#737);
#739=EDGE_CURVE('E397',#738,#729,#736,.T.);
#740=ORIENTED_EDGE('',*,*,#739,.F.);
#741=DIRECTION('',(0.,0.,-1.));
#742=VECTOR('',#741,1.);
#743=CARTESIAN_POINT('',(7.,-26.,2982.82253835));
#744=LINE('',#743,#742);
#745=CARTESIAN_POINT('',(7.,-26.,6036.256018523));
#746=VERTEX_POINT('',#745);
#747=EDGE_CURVE('E388',#746,#738,#744,.T.);
#748=ORIENTED_EDGE('',*,*,#747,.F.);
#749=DIRECTION('',(-1.,0.,0.));
#750=VECTOR('',#749,1.);
#751=CARTESIAN_POINT('',(-35.5,-26.,6036.256018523));
#752=LINE('',#751,#750);
#753=EDGE_CURVE('E376',#662,#746,#752,.T.);
#754=ORIENTED_EDGE('',*,*,#753,.F.);
#755=ORIENTED_EDGE('',*,*,#663,.F.);
#756=DIRECTION('',(1.,0.,0.));
#757=VECTOR('',#756,1.);
#758=CARTESIAN_POINT('',(-26.,-26.,0.));
#759=LINE('',#758,#757);
#760=CARTESIAN_POINT('',(7.,-26.,0.));
#761=VERTEX_POINT('',#760);
#762=EDGE_CURVE('E681',#761,#654,#759,.T.);
#763=ORIENTED_EDGE('',*,*,#762,.F.);
#764=DIRECTION('',(0.,0.,-1.));
#765=VECTOR('',#764,1.);
#766=CARTESIAN_POINT('',(7.,-26.,-0.5));
#767=LINE('',#766,#765);
#768=CARTESIAN_POINT('',(7.,-26.,120.));
#769=VERTEX_POINT('',#768);
#770=EDGE_CURVE('E618',#769,#761,#767,.T.);
#771=ORIENTED_EDGE('',*,*,#770,.F.);
#772=CARTESIAN_POINT('',(0.,-26.,120.));
#773=DIRECTION('',(0.,1.,0.));
#774=DIRECTION('',(0.,0.,1.));
#775=AXIS2_PLACEMENT_3D('',#772,#773,#774);
#776=CIRCLE('',#775,7.);
#777=CARTESIAN_POINT('',(0.,-26.,127.));
#778=VERTEX_POINT('',#777);
#779=EDGE_CURVE('E614',#778,#769,#776,.T.);
#780=ORIENTED_EDGE('',*,*,#779,.F.);
#781=CARTESIAN_POINT('',(0.,-26.,120.));
#782=DIRECTION('',(0.,1.,0.));
#783=DIRECTION('',(0.,0.,1.));
#784=AXIS2_PLACEMENT_3D('',#781,#782,#783);
#785=CIRCLE('',#784,7.);
#786=CARTESIAN_POINT('',(-7.,-26.,120.));
#787=VERTEX_POINT('',#786);
#788=EDGE_CURVE('E712',#787,#778,#785,.T.);
#789=ORIENTED_EDGE('',*,*,#788,.F.);
#790=DIRECTION('',(0.,0.,-1.));
#791=VECTOR('',#790,1.);
#792=CARTESIAN_POINT('',(-7.,-26.,-0.5));
#793=LINE('',#792,#791);
#794=EDGE_CURVE('E706',#787,#689,#793,.T.);
#795=ORIENTED_EDGE('',*,*,#794,.T.);
#796=EDGE_LOOP('',(#691,#699,#708,#714,#715,#723,#731,#740,#748,#754,#755,#763,#771,#780,#789,#795));
#797=FACE_BOUND('',#796,.T.);
#798=ADVANCED_FACE('F808',(#797),#681,.T.);
#799=CARTESIAN_POINT('',(-13.,-4.505685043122,-31.99529343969));
#800=DIRECTION('',(-1.,0.,0.));
#801=DIRECTION('',(0.,0.,1.));
#802=AXIS2_PLACEMENT_3D('',#799,#800,#801);
#803=PLANE('',#802);
#804=DIRECTION('',(0.,-0.867615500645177,0.497235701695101));
#805=VECTOR('',#804,1.);
#806=CARTESIAN_POINT('',(-13.,25.328457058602,20.061636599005));
#807=LINE('',#806,#805);
#808=CARTESIAN_POINT('',(-13.,-30.,51.770710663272));
#809=VERTEX_POINT('',#808);
#810=EDGE_CURVE('E457',#697,#809,#807,.T.);
#811=ORIENTED_EDGE('',*,*,#810,.F.);
#812=ORIENTED_EDGE('',*,*,#698,.F.);
#813=DIRECTION('',(0.,-1.,0.));
#814=VECTOR('',#813,1.);
#815=CARTESIAN_POINT('',(-13.,-2.252842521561,0.));
#816=LINE('',#815,#814);
#817=CARTESIAN_POINT('',(-13.,-30.,0.));
#818=VERTEX_POINT('',#817);
#819=EDGE_CURVE('E694',#687,#818,#816,.T.);
#820=ORIENTED_EDGE('',*,*,#819,.T.);
#821=DIRECTION('',(0.,0.,1.));
#822=VECTOR('',#821,1.);
#823=CARTESIAN_POINT('',(-13.,-30.,-15.99764671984));
#824=LINE('',#823,#822);
#825=EDGE_CURVE('E667',#818,#809,#824,.T.);
#826=ORIENTED_EDGE('',*,*,#825,.T.);
#827=EDGE_LOOP('',(#811,#812,#820,#826));
#828=FACE_BOUND('',#827,.T.);
#829=ADVANCED_FACE('F793',(#828),#803,.T.);
#830=CARTESIAN_POINT('',(-15.,25.328457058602,20.061636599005));
#831=DIRECTION('',(0.,-0.867615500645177,0.497235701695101));
#832=DIRECTION('',(0.,-0.497235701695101,-0.867615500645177));
#833=AXIS2_PLACEMENT_3D('',#830,#831,#832);
#834=CYLINDRICAL_SURFACE('',#833,2.);
#835=CARTESIAN_POINT('',(-15.,-30.,51.770710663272));
#836=DIRECTION('',(0.,1.,0.));
#837=DIRECTION('',(0.,0.,1.));
#838=AXIS2_PLACEMENT_3D('',#835,#836,#837);
#839=ELLIPSE('',#838,2.305168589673,2.);
#840=CARTESIAN_POINT('',(-15.,-30.,54.075879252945));
#841=VERTEX_POINT('',#840);
#842=EDGE_CURVE('E663',#841,#809,#839,.T.);
#843=ORIENTED_EDGE('',*,*,#842,.F.);
#844=DIRECTION('',(0.,-0.867615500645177,0.497235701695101));
#845=VECTOR('',#844,1.);
#846=CARTESIAN_POINT('',(-15.,26.322928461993,21.796867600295));
#847=LINE('',#846,#845);
#848=EDGE_CURVE('E438',#706,#841,#847,.T.);
#849=ORIENTED_EDGE('',*,*,#848,.F.);
#850=ORIENTED_EDGE('',*,*,#707,.T.);
#851=ORIENTED_EDGE('',*,*,#810,.T.);
#852=EDGE_LOOP('',(#843,#849,#850,#851));
#853=FACE_BOUND('',#852,.T.);
#854=ADVANCED_FACE('F804',(#853),#834,.F.);
#855=CARTESIAN_POINT('',(-15.,26.322928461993,21.796867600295));
#856=DIRECTION('',(0.,-0.497235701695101,-0.867615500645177));
#857=DIRECTION('',(0.,-0.867615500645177,0.497235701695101));
#858=AXIS2_PLACEMENT_3D('',#855,#856,#857);
#859=PLANE('',#858);
#860=ORIENTED_EDGE('',*,*,#713,.F.);
#861=ORIENTED_EDGE('',*,*,#848,.T.);
#862=DIRECTION('',(-1.,0.,0.));
#863=VECTOR('',#862,1.);
#864=CARTESIAN_POINT('',(-22.5,-30.,54.075879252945));
#865=LINE('',#864,#863);
#866=CARTESIAN_POINT('',(-30.,-30.,54.075879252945));
#867=VERTEX_POINT('',#866);
#868=EDGE_CURVE('E633',#841,#867,#865,.T.);
#869=ORIENTED_EDGE('',*,*,#868,.T.);
#870=DIRECTION('',(0.,0.867615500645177,-0.497235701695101));
#871=VECTOR('',#870,1.);
#872=CARTESIAN_POINT('',(-30.,32.408585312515,18.309140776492));
#873=LINE('',#872,#871);
#874=EDGE_CURVE('E437',#867,#437,#873,.T.);
#875=ORIENTED_EDGE('',*,*,#874,.T.);
#876=ORIENTED_EDGE('',*,*,#438,.F.);
#877=ORIENTED_EDGE('',*,*,#525,.F.);
#878=EDGE_LOOP('',(#860,#861,#869,#875,#876,#877));
#879=FACE_BOUND('',#878,.T.);
#880=ADVANCED_FACE('F963',(#879),#859,.T.);
#881=CARTESIAN_POINT('',(-30.,30.,0.));
#882=DIRECTION('',(1.,0.,0.));
#883=DIRECTION('',(0.,1.,0.));
#884=AXIS2_PLACEMENT_3D('',#881,#882,#883);
#885=PLANE('',#884);
#886=ORIENTED_EDGE('',*,*,#874,.F.);
#887=DIRECTION('',(0.,0.,1.));
#888=VECTOR('',#887,1.);
#889=CARTESIAN_POINT('',(-30.,-30.,0.));
#890=LINE('',#889,#888);
#891=CARTESIAN_POINT('',(-30.,-30.,6029.276507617));
#892=VERTEX_POINT('',#891);
#893=EDGE_CURVE('E629',#867,#892,#890,.T.);
#894=ORIENTED_EDGE('',*,*,#893,.T.);
#895=DIRECTION('',(0.,0.497235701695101,0.867615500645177));
#896=VECTOR('',#895,1.);
#897=CARTESIAN_POINT('',(-30.,-1330.131213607,3760.706511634));
#898=LINE('',#897,#896);
#899=EDGE_CURVE('E702',#892,#476,#898,.T.);
#900=ORIENTED_EDGE('',*,*,#899,.T.);
#901=ORIENTED_EDGE('',*,*,#477,.F.);
#902=ORIENTED_EDGE('',*,*,#584,.F.);
#903=ORIENTED_EDGE('',*,*,#446,.T.);
#904=EDGE_LOOP('',(#886,#894,#900,#901,#902,#903));
#905=FACE_BOUND('',#904,.T.);
#906=ADVANCED_FACE('F772',(#905),#885,.F.);
#907=CARTESIAN_POINT('',(-45.,-44.01045355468,6004.829979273));
#908=DIRECTION('',(0.,0.867615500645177,-0.497235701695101));
#909=DIRECTION('',(-1.,0.,0.));
#910=AXIS2_PLACEMENT_3D('',#907,#908,#909);
#911=PLANE('',#910);
#912=ORIENTED_EDGE('',*,*,#722,.T.);
#913=ORIENTED_EDGE('',*,*,#511,.T.);
#914=ORIENTED_EDGE('',*,*,#485,.T.);
#915=ORIENTED_EDGE('',*,*,#899,.F.);
#916=DIRECTION('',(-1.,0.,0.));
#917=VECTOR('',#916,1.);
#918=CARTESIAN_POINT('',(-37.5,-30.,6029.276507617));
#919=LINE('',#918,#917);
#920=CARTESIAN_POINT('',(-7.,-30.,6029.276507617));
#921=VERTEX_POINT('',#920);
#922=EDGE_CURVE('E634',#921,#892,#919,.T.);
#923=ORIENTED_EDGE('',*,*,#922,.F.);
#924=DIRECTION('',(0.,0.497235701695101,0.867615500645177));
#925=VECTOR('',#924,1.);
#926=CARTESIAN_POINT('',(-7.,-51.96704228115,5990.946704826));
#927=LINE('',#926,#925);
#928=EDGE_CURVE('E403',#921,#721,#927,.T.);
#929=ORIENTED_EDGE('',*,*,#928,.T.);
#930=EDGE_LOOP('',(#912,#913,#914,#915,#923,#929));
#931=FACE_BOUND('',#930,.T.);
#932=ADVANCED_FACE('F962',(#931),#911,.F.);
#933=CARTESIAN_POINT('',(-7.,-40.,5965.6450767));
#934=DIRECTION('',(1.,0.,0.));
#935=DIRECTION('',(0.,1.,0.));
#936=AXIS2_PLACEMENT_3D('',#933,#934,#935);
#937=PLANE('',#936);
#938=ORIENTED_EDGE('',*,*,#730,.F.);
#939=ORIENTED_EDGE('',*,*,#928,.F.);
#940=DIRECTION('',(0.,0.,-1.));
#941=VECTOR('',#940,1.);
#942=CARTESIAN_POINT('',(-7.,-30.,2982.82253835));
#943=LINE('',#942,#941);
#944=CARTESIAN_POINT('',(-7.,-30.,5965.6450767));
#945=VERTEX_POINT('',#944);
#946=EDGE_CURVE('E656',#921,#945,#943,.T.);
#947=ORIENTED_EDGE('',*,*,#946,.T.);
#948=DIRECTION('',(0.,1.,0.));
#949=VECTOR('',#948,1.);
#950=CARTESIAN_POINT('',(-7.,-40.,5965.6450767));
#951=LINE('',#950,#949);
#952=EDGE_CURVE('E404',#945,#729,#951,.T.);
#953=ORIENTED_EDGE('',*,*,#952,.T.);
#954=EDGE_LOOP('',(#938,#939,#947,#953));
#955=FACE_BOUND('',#954,.T.);
#956=ADVANCED_FACE('F1018',(#955),#937,.T.);
#957=CARTESIAN_POINT('',(0.,-40.,5965.6450767));
#958=DIRECTION('',(0.,1.,0.));
#959=DIRECTION('',(0.,0.,1.));
#960=AXIS2_PLACEMENT_3D('',#957,#958,#959);
#961=CYLINDRICAL_SURFACE('',#960,7.);
#962=ORIENTED_EDGE('',*,*,#739,.T.);
#963=ORIENTED_EDGE('',*,*,#952,.F.);
#964=CARTESIAN_POINT('',(0.,-30.,5965.6450767));
#965=DIRECTION('',(0.,1.,0.));
#966=DIRECTION('',(0.,0.,1.));
#967=AXIS2_PLACEMENT_3D('',#964,#965,#966);
#968=CIRCLE('',#967,7.);
#969=CARTESIAN_POINT('',(7.,-30.,5965.6450767));
#970=VERTEX_POINT('',#969);
#971=EDGE_CURVE('E652',#970,#945,#968,.T.);
#972=ORIENTED_EDGE('',*,*,#971,.F.);
#973=DIRECTION('',(0.,1.,0.));
#974=VECTOR('',#973,1.);
#975=CARTESIAN_POINT('',(7.,-40.,5965.6450767));
#976=LINE('',#975,#974);
#977=EDGE_CURVE('E384',#970,#738,#976,.T.);
#978=ORIENTED_EDGE('',*,*,#977,.T.);
#979=EDGE_LOOP('',(#962,#963,#972,#978));
#980=FACE_BOUND('',#979,.T.);
#981=ADVANCED_FACE('F986',(#980),#961,.F.);
#982=CARTESIAN_POINT('',(7.,-40.,5965.6450767));
#983=DIRECTION('',(1.,0.,0.));
#984=DIRECTION('',(0.,1.,0.));
#985=AXIS2_PLACEMENT_3D('',#982,#983,#984);
#986=PLANE('',#985);
#987=ORIENTED_EDGE('',*,*,#977,.F.);
#988=DIRECTION('',(0.,0.,-1.));
#989=VECTOR('',#988,1.);
#990=CARTESIAN_POINT('',(7.,-30.,2982.82253835));
#991=LINE('',#990,#989);
#992=CARTESIAN_POINT('',(7.,-30.,6029.276507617));
#993=VERTEX_POINT('',#992);
#994=EDGE_CURVE('E643',#993,#970,#991,.T.);
#995=ORIENTED_EDGE('',*,*,#994,.F.);
#996=DIRECTION('',(0.,0.497235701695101,0.867615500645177));
#997=VECTOR('',#996,1.);
#998=CARTESIAN_POINT('',(7.,-51.96704228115,5990.946704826));
#999=LINE('',#998,#997);
#1000=EDGE_CURVE('E380',#993,#746,#999,.T.);
#1001=ORIENTED_EDGE('',*,*,#1000,.T.);
#1002=ORIENTED_EDGE('',*,*,#747,.T.);
#1003=EDGE_LOOP('',(#987,#995,#1001,#1002));
#1004=FACE_BOUND('',#1003,.T.);
#1005=ADVANCED_FACE('F981',(#1004),#986,.F.);
#1006=CARTESIAN_POINT('',(-45.,-44.01045355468,6004.829979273));
#1007=DIRECTION('',(0.,0.867615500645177,-0.497235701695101));
#1008=DIRECTION('',(-1.,0.,0.));
#1009=AXIS2_PLACEMENT_3D('',#1006,#1007,#1008);
#1010=PLANE('',#1009);
#1011=ORIENTED_EDGE('',*,*,#549,.T.);
#1012=ORIENTED_EDGE('',*,*,#669,.T.);
#1013=ORIENTED_EDGE('',*,*,#753,.T.);
#1014=ORIENTED_EDGE('',*,*,#1000,.F.);
#1015=DIRECTION('',(-1.,0.,0.));
#1016=VECTOR('',#1015,1.);
#1017=CARTESIAN_POINT('',(-37.5,-30.,6029.276507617));
#1018=LINE('',#1017,#1016);
#1019=CARTESIAN_POINT('',(30.,-30.,6029.276507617));
#1020=VERTEX_POINT('',#1019);
#1021=EDGE_CURVE('E350',#1020,#993,#1018,.T.);
#1022=ORIENTED_EDGE('',*,*,#1021,.F.);
#1023=DIRECTION('',(0.,-0.497235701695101,-0.867615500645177));
#1024=VECTOR('',#1023,1.);
#1025=CARTESIAN_POINT('',(30.,-1337.548513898,3747.764229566));
#1026=LINE('',#1025,#1024);
#1027=EDGE_CURVE('E345',#548,#1020,#1026,.T.);
#1028=ORIENTED_EDGE('',*,*,#1027,.F.);
#1029=EDGE_LOOP('',(#1011,#1012,#1013,#1014,#1022,#1028));
#1030=FACE_BOUND('',#1029,.T.);
#1031=ADVANCED_FACE('F348',(#1030),#1010,.F.);
#1032=CARTESIAN_POINT('',(30.,-30.,0.));
#1033=DIRECTION('',(-1.,0.,0.));
#1034=DIRECTION('',(0.,0.,1.));
#1035=AXIS2_PLACEMENT_3D('',#1032,#1033,#1034);
#1036=PLANE('',#1035);
#1037=ORIENTED_EDGE('',*,*,#625,.T.);
#1038=ORIENTED_EDGE('',*,*,#600,.T.);
#1039=ORIENTED_EDGE('',*,*,#557,.F.);
#1040=ORIENTED_EDGE('',*,*,#1027,.T.);
#1041=DIRECTION('',(0.,0.,1.));
#1042=VECTOR('',#1041,1.);
#1043=CARTESIAN_POINT('',(30.,-30.,0.));
#1044=LINE('',#1043,#1042);
#1045=CARTESIAN_POINT('',(30.,-30.,0.));
#1046=VERTEX_POINT('',#1045);
#1047=EDGE_CURVE('E603',#1046,#1020,#1044,.T.);
#1048=ORIENTED_EDGE('',*,*,#1047,.F.);
#1049=DIRECTION('',(0.,1.,0.));
#1050=VECTOR('',#1049,1.);
#1051=CARTESIAN_POINT('',(30.,-30.,0.));
#1052=LINE('',#1051,#1050);
#1053=EDGE_CURVE('E740',#1046,#624,#1052,.T.);
#1054=ORIENTED_EDGE('',*,*,#1053,.T.);
#1055=EDGE_LOOP('',(#1037,#1038,#1039,#1040,#1048,#1054));
#1056=FACE_BOUND('',#1055,.T.);
#1057=ADVANCED_FACE('F357',(#1056),#1036,.F.);
#1058=CARTESIAN_POINT('',(0.,0.,0.));
#1059=DIRECTION('',(0.,0.,1.));
#1060=DIRECTION('',(1.,0.,0.));
#1061=AXIS2_PLACEMENT_3D('',#1058,#1059,#1060);
#1062=PLANE('',#1061);
#1063=ORIENTED_EDGE('',*,*,#762,.T.);
#1064=ORIENTED_EDGE('',*,*,#655,.T.);
#1065=ORIENTED_EDGE('',*,*,#633,.T.);
#1066=ORIENTED_EDGE('',*,*,#1053,.F.);
#1067=DIRECTION('',(1.,0.,0.));
#1068=VECTOR('',#1067,1.);
#1069=CARTESIAN_POINT('',(-30.,-30.,0.));
#1070=LINE('',#1069,#1068);
#1071=CARTESIAN_POINT('',(7.,-30.,0.));
#1072=VERTEX_POINT('',#1071);
#1073=EDGE_CURVE('E600',#1072,#1046,#1070,.T.);
#1074=ORIENTED_EDGE('',*,*,#1073,.F.);
#1075=DIRECTION('',(0.,1.,0.));
#1076=VECTOR('',#1075,1.);
#1077=CARTESIAN_POINT('',(7.,-20.,0.));
#1078=LINE('',#1077,#1076);
#1079=EDGE_CURVE('E677',#1072,#761,#1078,.T.);
#1080=ORIENTED_EDGE('',*,*,#1079,.T.);
#1081=EDGE_LOOP('',(#1063,#1064,#1065,#1066,#1074,#1080));
#1082=FACE_BOUND('',#1081,.T.);
#1083=ADVANCED_FACE('F1010',(#1082),#1062,.F.);
#1084=CARTESIAN_POINT('',(7.,-40.,-1.));
#1085=DIRECTION('',(1.,0.,0.));
#1086=DIRECTION('',(0.,1.,0.));
#1087=AXIS2_PLACEMENT_3D('',#1084,#1085,#1086);
#1088=PLANE('',#1087);
#1089=ORIENTED_EDGE('',*,*,#770,.T.);
#1090=ORIENTED_EDGE('',*,*,#1079,.F.);
#1091=DIRECTION('',(0.,0.,-1.));
#1092=VECTOR('',#1091,1.);
#1093=CARTESIAN_POINT('',(7.,-30.,-0.5));
#1094=LINE('',#1093,#1092);
#1095=CARTESIAN_POINT('',(7.,-30.,120.));
#1096=VERTEX_POINT('',#1095);
#1097=EDGE_CURVE('E604',#1096,#1072,#1094,.T.);
#1098=ORIENTED_EDGE('',*,*,#1097,.F.);
#1099=DIRECTION('',(0.,1.,0.));
#1100=VECTOR('',#1099,1.);
#1101=CARTESIAN_POINT('',(7.,-40.,120.));
#1102=LINE('',#1101,#1100);
#1103=EDGE_CURVE('E619',#1096,#769,#1102,.T.);
#1104=ORIENTED_EDGE('',*,*,#1103,.T.);
#1105=EDGE_LOOP('',(#1089,#1090,#1098,#1104));
#1106=FACE_BOUND('',#1105,.T.);
#1107=ADVANCED_FACE('F1034',(#1106),#1088,.F.);
#1108=CARTESIAN_POINT('',(0.,-40.,120.));
#1109=DIRECTION('',(0.,1.,0.));
#1110=DIRECTION('',(0.,0.,1.));
#1111=AXIS2_PLACEMENT_3D('',#1108,#1109,#1110);
#1112=CYLINDRICAL_SURFACE('',#1111,7.);
#1113=ORIENTED_EDGE('',*,*,#1103,.F.);
#1114=CARTESIAN_POINT('',(0.,-30.,120.));
#1115=DIRECTION('',(0.,1.,0.));
#1116=DIRECTION('',(0.,0.,1.));
#1117=AXIS2_PLACEMENT_3D('',#1114,#1115,#1116);
#1118=CIRCLE('',#1117,7.);
#1119=CARTESIAN_POINT('',(0.,-30.,127.));
#1120=VERTEX_POINT('',#1119);
#1121=EDGE_CURVE('E612',#1120,#1096,#1118,.T.);
#1122=ORIENTED_EDGE('',*,*,#1121,.F.);
#1123=DIRECTION('',(0.,1.,0.));
#1124=VECTOR('',#1123,1.);
#1125=CARTESIAN_POINT('',(0.,-40.,127.));
#1126=LINE('',#1125,#1124);
#1127=EDGE_CURVE('E716',#1120,#778,#1126,.T.);
#1128=ORIENTED_EDGE('',*,*,#1127,.T.);
#1129=ORIENTED_EDGE('',*,*,#779,.T.);
#1130=EDGE_LOOP('',(#1113,#1122,#1128,#1129));
#1131=FACE_BOUND('',#1130,.T.);
#1132=ADVANCED_FACE('F1043',(#1131),#1112,.F.);
#1133=CARTESIAN_POINT('',(0.,-40.,120.));
#1134=DIRECTION('',(0.,1.,0.));
#1135=DIRECTION('',(0.,0.,1.));
#1136=AXIS2_PLACEMENT_3D('',#1133,#1134,#1135);
#1137=CYLINDRICAL_SURFACE('',#1136,7.);
#1138=CARTESIAN_POINT('',(0.,-30.,120.));
#1139=DIRECTION('',(0.,1.,0.));
#1140=DIRECTION('',(0.,0.,1.));
#1141=AXIS2_PLACEMENT_3D('',#1138,#1139,#1140);
#1142=CIRCLE('',#1141,7.);
#1143=CARTESIAN_POINT('',(-7.,-30.,120.));
#1144=VERTEX_POINT('',#1143);
#1145=EDGE_CURVE('E608',#1144,#1120,#1142,.T.);
#1146=ORIENTED_EDGE('',*,*,#1145,.F.);
#1147=DIRECTION('',(0.,1.,0.));
#1148=VECTOR('',#1147,1.);
#1149=CARTESIAN_POINT('',(-7.,-40.,120.));
#1150=LINE('',#1149,#1148);
#1151=EDGE_CURVE('E698',#1144,#787,#1150,.T.);
#1152=ORIENTED_EDGE('',*,*,#1151,.T.);
#1153=ORIENTED_EDGE('',*,*,#788,.T.);
#1154=ORIENTED_EDGE('',*,*,#1127,.F.);
#1155=EDGE_LOOP('',(#1146,#1152,#1153,#1154));
#1156=FACE_BOUND('',#1155,.T.);
#1157=ADVANCED_FACE('F826',(#1156),#1137,.F.);
#1158=CARTESIAN_POINT('',(-7.,-40.,-1.));
#1159=DIRECTION('',(1.,0.,0.));
#1160=DIRECTION('',(0.,1.,0.));
#1161=AXIS2_PLACEMENT_3D('',#1158,#1159,#1160);
#1162=PLANE('',#1161);
#1163=ORIENTED_EDGE('',*,*,#1151,.F.);
#1164=DIRECTION('',(0.,0.,-1.));
#1165=VECTOR('',#1164,1.);
#1166=CARTESIAN_POINT('',(-7.,-30.,-0.5));
#1167=LINE('',#1166,#1165);
#1168=CARTESIAN_POINT('',(-7.,-30.,0.));
#1169=VERTEX_POINT('',#1168);
#1170=EDGE_CURVE('E613',#1144,#1169,#1167,.T.);
#1171=ORIENTED_EDGE('',*,*,#1170,.T.);
#1172=DIRECTION('',(0.,1.,0.));
#1173=VECTOR('',#1172,1.);
#1174=CARTESIAN_POINT('',(-7.,-20.,0.));
#1175=LINE('',#1174,#1173);
#1176=EDGE_CURVE('E690',#1169,#689,#1175,.T.);
#1177=ORIENTED_EDGE('',*,*,#1176,.T.);
#1178=ORIENTED_EDGE('',*,*,#794,.F.);
#1179=EDGE_LOOP('',(#1163,#1171,#1177,#1178));
#1180=FACE_BOUND('',#1179,.T.);
#1181=ADVANCED_FACE('F819',(#1180),#1162,.T.);
#1182=CARTESIAN_POINT('',(0.,0.,0.));
#1183=DIRECTION('',(0.,0.,1.));
#1184=DIRECTION('',(1.,0.,0.));
#1185=AXIS2_PLACEMENT_3D('',#1182,#1183,#1184);
#1186=PLANE('',#1185);
#1187=ORIENTED_EDGE('',*,*,#690,.T.);
#1188=ORIENTED_EDGE('',*,*,#1176,.F.);
#1189=DIRECTION('',(1.,0.,0.));
#1190=VECTOR('',#1189,1.);
#1191=CARTESIAN_POINT('',(-30.,-30.,0.));
#1192=LINE('',#1191,#1190);
#1193=EDGE_CURVE('E682',#818,#1169,#1192,.T.);
#1194=ORIENTED_EDGE('',*,*,#1193,.F.);
#1195=ORIENTED_EDGE('',*,*,#819,.F.);
#1196=EDGE_LOOP('',(#1187,#1188,#1194,#1195));
#1197=FACE_BOUND('',#1196,.T.);
#1198=ADVANCED_FACE('F810',(#1197),#1186,.F.);
#1199=CARTESIAN_POINT('',(-30.,-30.,0.));
#1200=DIRECTION('',(0.,1.,0.));
#1201=DIRECTION('',(1.,0.,0.));
#1202=AXIS2_PLACEMENT_3D('',#1199,#1200,#1201);
#1203=PLANE('',#1202);
#1204=ORIENTED_EDGE('',*,*,#1170,.F.);
#1205=ORIENTED_EDGE('',*,*,#1145,.T.);
#1206=ORIENTED_EDGE('',*,*,#1121,.T.);
#1207=ORIENTED_EDGE('',*,*,#1097,.T.);
#1208=ORIENTED_EDGE('',*,*,#1073,.T.);
#1209=ORIENTED_EDGE('',*,*,#1047,.T.);
#1210=ORIENTED_EDGE('',*,*,#1021,.T.);
#1211=ORIENTED_EDGE('',*,*,#994,.T.);
#1212=ORIENTED_EDGE('',*,*,#971,.T.);
#1213=ORIENTED_EDGE('',*,*,#946,.F.);
#1214=ORIENTED_EDGE('',*,*,#922,.T.);
#1215=ORIENTED_EDGE('',*,*,#893,.F.);
#1216=ORIENTED_EDGE('',*,*,#868,.F.);
#1217=ORIENTED_EDGE('',*,*,#842,.T.);
#1218=ORIENTED_EDGE('',*,*,#825,.F.);
#1219=ORIENTED_EDGE('',*,*,#1193,.T.);
#1220=EDGE_LOOP('',(#1204,#1205,#1206,#1207,#1208,#1209,#1210,#1211,#1212,#1213,#1214,#1215,
#1216,#1217,#1218,#1219));
#1221=FACE_BOUND('',#1220,.T.);
#1222=ADVANCED_FACE('F800',(#1221),#1203,.F.);
#1223=CLOSED_SHELL('',(#58,#91,#122,#153,#184,#217,#257,#290,#323,#354,#416,#456,#496,#529,#569,
#610,#643,#676,#798,#829,#854,#880,#906,#932,#956,#981,#1005,#1031,#1057,#1083,#1107,#1132,
#1157,#1181,#1198,#1222));
#1224=MANIFOLD_SOLID_BREP('B1',#1223);
#1225=ADVANCED_BREP_SHAPE_REPRESENTATION('',(#18,#1224),#14);
#1226=SHAPE_DEFINITION_REPRESENTATION(#9,#1225);
ENDSEC;
END-ISO-10303-21;
